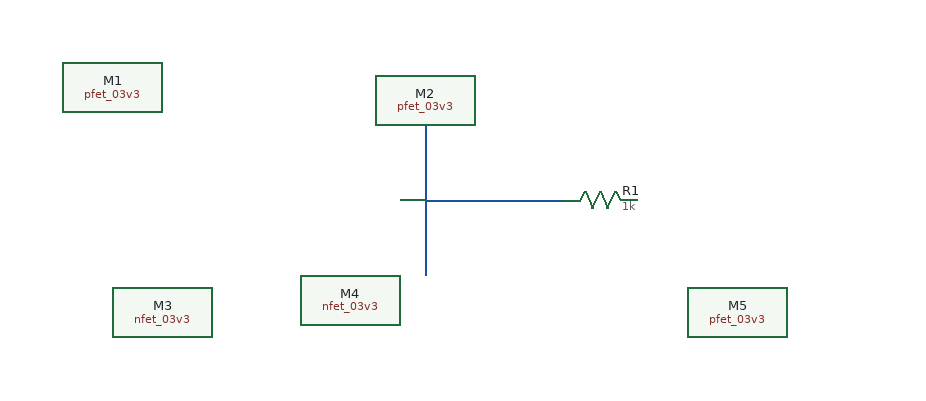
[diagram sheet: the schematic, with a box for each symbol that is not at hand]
v {xschem version=3.4.8RC file_version=1.3}
G {}
K {}
V {}
S {}
F {}
E {}
N 870 -590 870 -470 {lab=#net1}
N 870 -530 980 -530 {lab=#net1}
C {title.sym} 160 -40 0 0 {name=l1 author="Yi-Hsiang Wei"}
C {symbols/nfet_03v3.sym} 850 -440 0 0 {name=M4
L=0.28u
W=0.22u
nf=1
m=1
ad="'int((nf+1)/2) * W/nf * 0.18u'"
pd="'2*int((nf+1)/2) * (W/nf + 0.18u)'"
as="'int((nf+2)/2) * W/nf * 0.18u'"
ps="'2*int((nf+2)/2) * (W/nf + 0.18u)'"
nrd="'0.18u / W'" nrs="'0.18u / W'"
sa=0 sb=0 sd=0
model=nfet_03v3
spiceprefix=X
}
C {symbols/nfet_03v3.sym} 660 -440 0 1 {name=M3
L=0.28u
W=0.22u
nf=1
m=1
ad="'int((nf+1)/2) * W/nf * 0.18u'"
pd="'2*int((nf+1)/2) * (W/nf + 0.18u)'"
as="'int((nf+2)/2) * W/nf * 0.18u'"
ps="'2*int((nf+2)/2) * (W/nf + 0.18u)'"
nrd="'0.18u / W'" nrs="'0.18u / W'"
sa=0 sb=0 sd=0
model=nfet_03v3
spiceprefix=X
}
C {symbols/pfet_03v3.sym} 620 -620 0 0 {name=M1
L=0.28u
W=0.22u
nf=1
m=1
ad="'int((nf+1)/2) * W/nf * 0.18u'"
pd="'2*int((nf+1)/2) * (W/nf + 0.18u)'"
as="'int((nf+2)/2) * W/nf * 0.18u'"
ps="'2*int((nf+2)/2) * (W/nf + 0.18u)'"
nrd="'0.18u / W'" nrs="'0.18u / W'"
sa=0 sb=0 sd=0
model=pfet_03v3
spiceprefix=X
}
C {symbols/pfet_03v3.sym} 890 -620 0 1 {name=M2
L=0.28u
W=0.22u
nf=1
m=1
ad="'int((nf+1)/2) * W/nf * 0.18u'"
pd="'2*int((nf+1)/2) * (W/nf + 0.18u)'"
as="'int((nf+2)/2) * W/nf * 0.18u'"
ps="'2*int((nf+2)/2) * (W/nf + 0.18u)'"
nrd="'0.18u / W'" nrs="'0.18u / W'"
sa=0 sb=0 sd=0
model=pfet_03v3
spiceprefix=X
}
C {symbols/pfet_03v3.sym} 1120 -440 0 0 {name=M5
L=0.28u
W=0.22u
nf=1
m=1
ad="'int((nf+1)/2) * W/nf * 0.18u'"
pd="'2*int((nf+1)/2) * (W/nf + 0.18u)'"
as="'int((nf+2)/2) * W/nf * 0.18u'"
ps="'2*int((nf+2)/2) * (W/nf + 0.18u)'"
nrd="'0.18u / W'" nrs="'0.18u / W'"
sa=0 sb=0 sd=0
model=pfet_03v3
spiceprefix=X
}
C {res.sym} 1010 -530 3 0 {name=R1
value=1k
footprint=1206
device=resistor
m=1}
